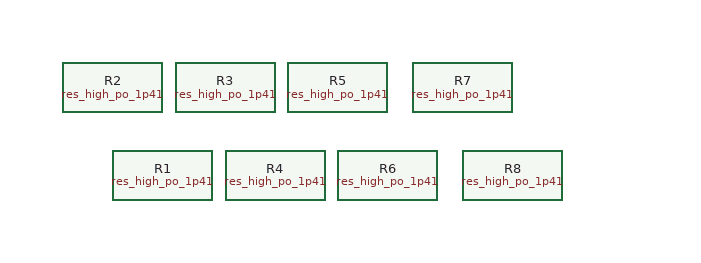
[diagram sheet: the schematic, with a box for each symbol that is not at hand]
v {xschem version=3.4.4 file_version=1.2
}
G {}
K {}
V {}
S {}
E {}
C {sky130_fd_pr/res_high_po_1p41.sym} -50 -30 3 0 {name=R2
L=49
model=res_high_po_1p41
spiceprefix=X
mult=1}
C {sky130_fd_pr/res_high_po_1p41.sym} -10 40 0 0 {name=R1
L=49
model=res_high_po_1p41
spiceprefix=X
mult=1}
C {sky130_fd_pr/res_high_po_1p41.sym} 40 -30 3 0 {name=R3
L=49
model=res_high_po_1p41
spiceprefix=X
mult=1}
C {sky130_fd_pr/res_high_po_1p41.sym} 80 40 0 0 {name=R4
L=49
model=res_high_po_1p41
spiceprefix=X
mult=1}
C {sky130_fd_pr/res_high_po_1p41.sym} 130 -30 3 0 {name=R5
L=49
model=res_high_po_1p41
spiceprefix=X
mult=1}
C {sky130_fd_pr/res_high_po_1p41.sym} 170 40 0 0 {name=R6
L=49
model=res_high_po_1p41
spiceprefix=X
mult=1}
C {sky130_fd_pr/res_high_po_1p41.sym} 230 -30 3 0 {name=R7
L=49
model=res_high_po_1p41
spiceprefix=X
mult=1}
C {sky130_fd_pr/res_high_po_1p41.sym} 270 40 0 0 {name=R8
L=49
model=res_high_po_1p41
spiceprefix=X
mult=1}
